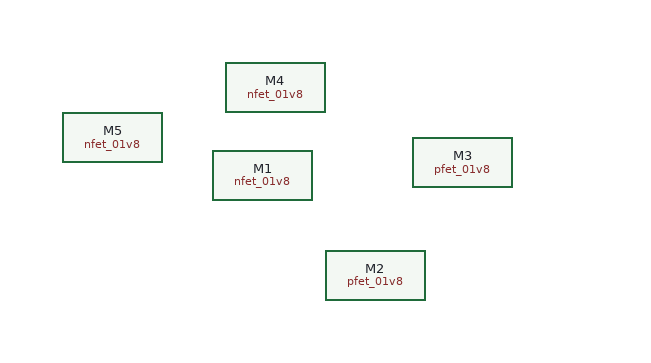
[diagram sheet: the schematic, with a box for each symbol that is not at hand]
v {xschem version=3.4.8RC file_version=1.3}
G {}
K {}
V {}
S {}
F {}
E {}
C {sky130_fd_pr/nfet_01v8.sym} -10 -10 0 0 {name=M1
W=1
L=0.15
nf=1 
mult=1
ad="expr('int((@nf + 1)/2) * @W / @nf * 0.29')"
pd="expr('2*int((@nf + 1)/2) * (@W / @nf + 0.29)')"
as="expr('int((@nf + 2)/2) * @W / @nf * 0.29')"
ps="expr('2*int((@nf + 2)/2) * (@W / @nf + 0.29)')"
nrd="expr('0.29 / @W ')" nrs="expr('0.29 / @W ')"
sa=0 sb=0 sd=0
model=nfet_01v8
spiceprefix=X
}
C {sky130_fd_pr/pfet_01v8.sym} 80 70 0 0 {name=M2
W=1
L=0.15
nf=1
mult=1
ad="expr('int((@nf + 1)/2) * @W / @nf * 0.29')"
pd="expr('2*int((@nf + 1)/2) * (@W / @nf + 0.29)')"
as="expr('int((@nf + 2)/2) * @W / @nf * 0.29')"
ps="expr('2*int((@nf + 2)/2) * (@W / @nf + 0.29)')"
nrd="expr('0.29 / @W ')" nrs="expr('0.29 / @W ')"
sa=0 sb=0 sd=0
model=pfet_01v8
spiceprefix=X
}
C {sky130_fd_pr/pfet_01v8.sym} 150 -20 0 0 {name=M3
W=1
L=0.15
nf=1
mult=1
ad="expr('int((@nf + 1)/2) * @W / @nf * 0.29')"
pd="expr('2*int((@nf + 1)/2) * (@W / @nf + 0.29)')"
as="expr('int((@nf + 2)/2) * @W / @nf * 0.29')"
ps="expr('2*int((@nf + 2)/2) * (@W / @nf + 0.29)')"
nrd="expr('0.29 / @W ')" nrs="expr('0.29 / @W ')"
sa=0 sb=0 sd=0
model=pfet_01v8
spiceprefix=X
}
C {sky130_fd_pr/nfet_01v8.sym} 0 -80 0 0 {name=M4
W=1
L=0.15
nf=1 
mult=1
ad="expr('int((@nf + 1)/2) * @W / @nf * 0.29')"
pd="expr('2*int((@nf + 1)/2) * (@W / @nf + 0.29)')"
as="expr('int((@nf + 2)/2) * @W / @nf * 0.29')"
ps="expr('2*int((@nf + 2)/2) * (@W / @nf + 0.29)')"
nrd="expr('0.29 / @W ')" nrs="expr('0.29 / @W ')"
sa=0 sb=0 sd=0
model=nfet_01v8
spiceprefix=X
}
C {sky130_fd_pr/nfet_01v8.sym} -130 -40 0 0 {name=M5
W=1
L=0.15
nf=1 
mult=1
ad="expr('int((@nf + 1)/2) * @W / @nf * 0.29')"
pd="expr('2*int((@nf + 1)/2) * (@W / @nf + 0.29)')"
as="expr('int((@nf + 2)/2) * @W / @nf * 0.29')"
ps="expr('2*int((@nf + 2)/2) * (@W / @nf + 0.29)')"
nrd="expr('0.29 / @W ')" nrs="expr('0.29 / @W ')"
sa=0 sb=0 sd=0
model=nfet_01v8
spiceprefix=X
}
